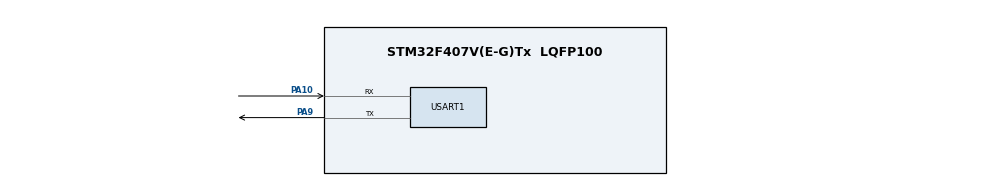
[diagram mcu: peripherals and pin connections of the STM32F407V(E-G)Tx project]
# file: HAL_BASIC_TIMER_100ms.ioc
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Mcu.Family=STM32F4
Mcu.Name=STM32F407V(E-G)Tx
Mcu.Package=LQFP100
NVIC.PriorityGroup=NVIC_PRIORITYGROUP_4
NVIC.RCC_IRQn=true\:0\:0\:false\:false\:true\:true\:false\:true
NVIC.USART1_IRQn=true\:0\:0\:false\:false\:true\:true\:true\:true
PA10.Mode=Asynchronous
PA10.Signal=USART1_RX
PA9.Mode=Asynchronous
PA9.Signal=USART1_TX
PH0-OSC_IN.Mode=HSE-External-Oscillator
PH0-OSC_IN.Signal=RCC_OSC_IN
PH1-OSC_OUT.Mode=HSE-External-Oscillator
PH1-OSC_OUT.Signal=RCC_OSC_OUT
ProjectManager.HeapSize=0x200
ProjectManager.StackSize=0x400
ProjectManager.TargetToolchain=CMake
RCC.AHBFreq_Value=8000000
RCC.APB1Freq_Value=8000000
RCC.APB1TimFreq_Value=8000000
RCC.APB2Freq_Value=8000000
RCC.APB2TimFreq_Value=8000000
RCC.CortexFreq_Value=8000000
RCC.HCLKFreq_Value=8000000
RCC.HSE_VALUE=8000000
RCC.HSI_VALUE=16000000
RCC.LSE_VALUE=32768
RCC.SYSCLKFreq_VALUE=8000000
RCC.SYSCLKSource=RCC_SYSCLKSOURCE_HSE
RCC.VCOOutputFreq_Value=192000000
USART1.VirtualMode=VM_ASYNC
VP_TIM6_VS_ClockSourceINT.Mode=Enable_Timer
board=custom

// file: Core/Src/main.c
/* USER CODE BEGIN Header */
/**
  ******************************************************************************
  * @file           : main.c
  * @brief          : Main program body
  ******************************************************************************
  * @attention
  *
  * Copyright (c) 2026 STMicroelectronics.
  * All rights reserved.
  *
  * This software is licensed under terms that can be found in the LICENSE file
  * in the root directory of this software component.
  * If no LICENSE file comes with this software, it is provided AS-IS.
  *
  ******************************************************************************
  */
/* USER CODE END Header */
#include "main.h"
#include "tim.h"
#include "usart.h"
#include "gpio.h"

/* USER CODE BEGIN Includes */
#include <stdio.h>
#include <string.h>
/* USER CODE END Includes */

void SystemClock_Config(void);

int main(void)
{

  /* MCU Configuration--------------------------------------------------------*/

  /* Reset of all peripherals, Initializes the Flash interface and the Systick. */
  HAL_Init();

  /* Configure the system clock */
  SystemClock_Config();

  /* Initialize all configured peripherals */
  MX_GPIO_Init();
  MX_TIM6_Init();
  MX_USART1_UART_Init();
  /* USER CODE BEGIN 2 */

  //Start the timer with Interrupt
  HAL_TIM_Base_Start_IT(&htim6);

  /* USER CODE END 2 */

  /* Infinite loop */
  while (1)
  {

  }
}

void SystemClock_Config(void)
{
  RCC_OscInitTypeDef RCC_OscInitStruct = {0};
  RCC_ClkInitTypeDef RCC_ClkInitStruct = {0};

  /** Configure the main internal regulator output voltage
  */
  __HAL_RCC_PWR_CLK_ENABLE();
  __HAL_PWR_VOLTAGESCALING_CONFIG(PWR_REGULATOR_VOLTAGE_SCALE1);

  /** Initializes the RCC Oscillators according to the specified parameters
  * in the RCC_OscInitTypeDef structure.
  */
  RCC_OscInitStruct.OscillatorType = RCC_OSCILLATORTYPE_HSI;
  RCC_OscInitStruct.HSIState = RCC_HSI_ON;
  RCC_OscInitStruct.PLL.PLLState = RCC_PLL_NONE;
  if (HAL_RCC_OscConfig(&RCC_OscInitStruct) != HAL_OK)
  {
    Error_Handler();
  }

  /** Initializes the CPU, AHB and APB buses clocks
  */
  RCC_ClkInitStruct.ClockType = RCC_CLOCKTYPE_HCLK|RCC_CLOCKTYPE_SYSCLK
                              |RCC_CLOCKTYPE_PCLK1|RCC_CLOCKTYPE_PCLK2;
  RCC_ClkInitStruct.SYSCLKSource = RCC_SYSCLKSOURCE_HSI;
  RCC_ClkInitStruct.AHBCLKDivider = RCC_SYSCLK_DIV1;
  RCC_ClkInitStruct.APB1CLKDivider = RCC_HCLK_DIV1;
  RCC_ClkInitStruct.APB2CLKDivider = RCC_HCLK_DIV1;

  if (HAL_RCC_ClockConfig(&RCC_ClkInitStruct, FLASH_LATENCY_0) != HAL_OK)
  {
    Error_Handler();
  }
}

/* USER CODE BEGIN 4 */
void HAL_TIM_PeriodElapsedCallback(TIM_HandleTypeDef *htim) {
  HAL_GPIO_TogglePin(GPIOA, GPIO_PIN_7);
}
/* USER CODE END 4 */

void Error_Handler(void)
{
  __disable_irq();
  while (1)
  {
  }
}
